VERSION 5.8 ;
BUSBITCHARS "[]" ;
DIVIDERCHAR "/" ;
UNITS
    DATABASE MICRONS 1000 ;
END UNITS

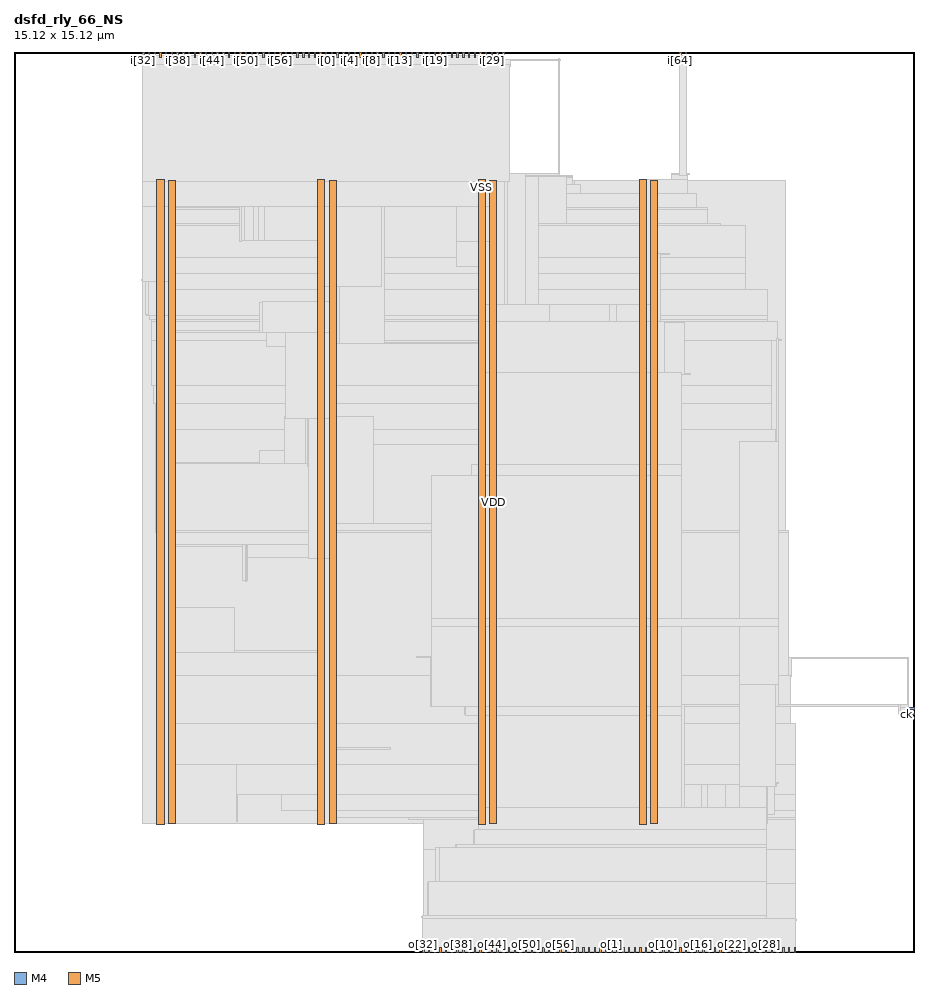
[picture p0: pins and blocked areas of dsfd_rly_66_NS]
MACRO dsfd_rly_66_NS
  FOREIGN dsfd_rly_66_NS 0 0 ;
  CLASS BLOCK ;
  SIZE 15.12 BY 15.12 ;
  PIN ck
    DIRECTION INPUT ;
    USE SIGNAL ;
    PORT
      LAYER M4 ;
        RECT  15.036 3.984 15.12 4.008 ;
    END
  END ck
  PIN i[0]
    DIRECTION INPUT ;
    USE SIGNAL ;
    PORT
      LAYER M5 ;
        RECT  5.232 15.036 5.256 15.12 ;
    END
  END i[0]
  PIN i[10]
    DIRECTION INPUT ;
    USE SIGNAL ;
    PORT
      LAYER M5 ;
        RECT  6.192 15.036 6.216 15.12 ;
    END
  END i[10]
  PIN i[11]
    DIRECTION INPUT ;
    USE SIGNAL ;
    PORT
      LAYER M5 ;
        RECT  6.288 15.036 6.312 15.12 ;
    END
  END i[11]
  PIN i[12]
    DIRECTION INPUT ;
    USE SIGNAL ;
    PORT
      LAYER M5 ;
        RECT  6.384 15.036 6.408 15.12 ;
    END
  END i[12]
  PIN i[13]
    DIRECTION INPUT ;
    USE SIGNAL ;
    PORT
      LAYER M5 ;
        RECT  6.48 15.036 6.504 15.12 ;
    END
  END i[13]
  PIN i[14]
    DIRECTION INPUT ;
    USE SIGNAL ;
    PORT
      LAYER M5 ;
        RECT  6.576 15.036 6.6 15.12 ;
    END
  END i[14]
  PIN i[15]
    DIRECTION INPUT ;
    USE SIGNAL ;
    PORT
      LAYER M5 ;
        RECT  6.672 15.036 6.696 15.12 ;
    END
  END i[15]
  PIN i[16]
    DIRECTION INPUT ;
    USE SIGNAL ;
    PORT
      LAYER M5 ;
        RECT  6.768 15.036 6.792 15.12 ;
    END
  END i[16]
  PIN i[17]
    DIRECTION INPUT ;
    USE SIGNAL ;
    PORT
      LAYER M5 ;
        RECT  6.864 15.036 6.888 15.12 ;
    END
  END i[17]
  PIN i[18]
    DIRECTION INPUT ;
    USE SIGNAL ;
    PORT
      LAYER M5 ;
        RECT  6.96 15.036 6.984 15.12 ;
    END
  END i[18]
  PIN i[19]
    DIRECTION INPUT ;
    USE SIGNAL ;
    PORT
      LAYER M5 ;
        RECT  7.056 15.036 7.08 15.12 ;
    END
  END i[19]
  PIN i[1]
    DIRECTION INPUT ;
    USE SIGNAL ;
    PORT
      LAYER M5 ;
        RECT  5.328 15.036 5.352 15.12 ;
    END
  END i[1]
  PIN i[20]
    DIRECTION INPUT ;
    USE SIGNAL ;
    PORT
      LAYER M5 ;
        RECT  7.152 15.036 7.176 15.12 ;
    END
  END i[20]
  PIN i[21]
    DIRECTION INPUT ;
    USE SIGNAL ;
    PORT
      LAYER M5 ;
        RECT  7.248 15.036 7.272 15.12 ;
    END
  END i[21]
  PIN i[22]
    DIRECTION INPUT ;
    USE SIGNAL ;
    PORT
      LAYER M5 ;
        RECT  7.344 15.036 7.368 15.12 ;
    END
  END i[22]
  PIN i[23]
    DIRECTION INPUT ;
    USE SIGNAL ;
    PORT
      LAYER M5 ;
        RECT  7.44 15.036 7.464 15.12 ;
    END
  END i[23]
  PIN i[24]
    DIRECTION INPUT ;
    USE SIGNAL ;
    PORT
      LAYER M5 ;
        RECT  7.536 15.036 7.56 15.12 ;
    END
  END i[24]
  PIN i[25]
    DIRECTION INPUT ;
    USE SIGNAL ;
    PORT
      LAYER M5 ;
        RECT  7.632 15.036 7.656 15.12 ;
    END
  END i[25]
  PIN i[26]
    DIRECTION INPUT ;
    USE SIGNAL ;
    PORT
      LAYER M5 ;
        RECT  7.728 15.036 7.752 15.12 ;
    END
  END i[26]
  PIN i[27]
    DIRECTION INPUT ;
    USE SIGNAL ;
    PORT
      LAYER M5 ;
        RECT  7.824 15.036 7.848 15.12 ;
    END
  END i[27]
  PIN i[28]
    DIRECTION INPUT ;
    USE SIGNAL ;
    PORT
      LAYER M5 ;
        RECT  7.92 15.036 7.944 15.12 ;
    END
  END i[28]
  PIN i[29]
    DIRECTION INPUT ;
    USE SIGNAL ;
    PORT
      LAYER M5 ;
        RECT  8.016 15.036 8.04 15.12 ;
    END
  END i[29]
  PIN i[2]
    DIRECTION INPUT ;
    USE SIGNAL ;
    PORT
      LAYER M5 ;
        RECT  5.424 15.036 5.448 15.12 ;
    END
  END i[2]
  PIN i[30]
    DIRECTION INPUT ;
    USE SIGNAL ;
    PORT
      LAYER M5 ;
        RECT  8.112 15.036 8.136 15.12 ;
    END
  END i[30]
  PIN i[31]
    DIRECTION INPUT ;
    USE SIGNAL ;
    PORT
      LAYER M5 ;
        RECT  8.208 15.036 8.232 15.12 ;
    END
  END i[31]
  PIN i[32]
    DIRECTION INPUT ;
    USE SIGNAL ;
    PORT
      LAYER M5 ;
        RECT  2.16 15.036 2.184 15.12 ;
    END
  END i[32]
  PIN i[33]
    DIRECTION INPUT ;
    USE SIGNAL ;
    PORT
      LAYER M5 ;
        RECT  2.256 15.036 2.28 15.12 ;
    END
  END i[33]
  PIN i[34]
    DIRECTION INPUT ;
    USE SIGNAL ;
    PORT
      LAYER M5 ;
        RECT  2.352 15.036 2.376 15.12 ;
    END
  END i[34]
  PIN i[35]
    DIRECTION INPUT ;
    USE SIGNAL ;
    PORT
      LAYER M5 ;
        RECT  2.448 15.036 2.472 15.12 ;
    END
  END i[35]
  PIN i[36]
    DIRECTION INPUT ;
    USE SIGNAL ;
    PORT
      LAYER M5 ;
        RECT  2.544 15.036 2.568 15.12 ;
    END
  END i[36]
  PIN i[37]
    DIRECTION INPUT ;
    USE SIGNAL ;
    PORT
      LAYER M5 ;
        RECT  2.64 15.036 2.664 15.12 ;
    END
  END i[37]
  PIN i[38]
    DIRECTION INPUT ;
    USE SIGNAL ;
    PORT
      LAYER M5 ;
        RECT  2.736 15.036 2.76 15.12 ;
    END
  END i[38]
  PIN i[39]
    DIRECTION INPUT ;
    USE SIGNAL ;
    PORT
      LAYER M5 ;
        RECT  2.832 15.036 2.856 15.12 ;
    END
  END i[39]
  PIN i[3]
    DIRECTION INPUT ;
    USE SIGNAL ;
    PORT
      LAYER M5 ;
        RECT  5.52 15.036 5.544 15.12 ;
    END
  END i[3]
  PIN i[40]
    DIRECTION INPUT ;
    USE SIGNAL ;
    PORT
      LAYER M5 ;
        RECT  2.928 15.036 2.952 15.12 ;
    END
  END i[40]
  PIN i[41]
    DIRECTION INPUT ;
    USE SIGNAL ;
    PORT
      LAYER M5 ;
        RECT  3.024 15.036 3.048 15.12 ;
    END
  END i[41]
  PIN i[42]
    DIRECTION INPUT ;
    USE SIGNAL ;
    PORT
      LAYER M5 ;
        RECT  3.12 15.036 3.144 15.12 ;
    END
  END i[42]
  PIN i[43]
    DIRECTION INPUT ;
    USE SIGNAL ;
    PORT
      LAYER M5 ;
        RECT  3.216 15.036 3.24 15.12 ;
    END
  END i[43]
  PIN i[44]
    DIRECTION INPUT ;
    USE SIGNAL ;
    PORT
      LAYER M5 ;
        RECT  3.312 15.036 3.336 15.12 ;
    END
  END i[44]
  PIN i[45]
    DIRECTION INPUT ;
    USE SIGNAL ;
    PORT
      LAYER M5 ;
        RECT  3.408 15.036 3.432 15.12 ;
    END
  END i[45]
  PIN i[46]
    DIRECTION INPUT ;
    USE SIGNAL ;
    PORT
      LAYER M5 ;
        RECT  3.504 15.036 3.528 15.12 ;
    END
  END i[46]
  PIN i[47]
    DIRECTION INPUT ;
    USE SIGNAL ;
    PORT
      LAYER M5 ;
        RECT  3.6 15.036 3.624 15.12 ;
    END
  END i[47]
  PIN i[48]
    DIRECTION INPUT ;
    USE SIGNAL ;
    PORT
      LAYER M5 ;
        RECT  3.696 15.036 3.72 15.12 ;
    END
  END i[48]
  PIN i[49]
    DIRECTION INPUT ;
    USE SIGNAL ;
    PORT
      LAYER M5 ;
        RECT  3.792 15.036 3.816 15.12 ;
    END
  END i[49]
  PIN i[4]
    DIRECTION INPUT ;
    USE SIGNAL ;
    PORT
      LAYER M5 ;
        RECT  5.616 15.036 5.64 15.12 ;
    END
  END i[4]
  PIN i[50]
    DIRECTION INPUT ;
    USE SIGNAL ;
    PORT
      LAYER M5 ;
        RECT  3.888 15.036 3.912 15.12 ;
    END
  END i[50]
  PIN i[51]
    DIRECTION INPUT ;
    USE SIGNAL ;
    PORT
      LAYER M5 ;
        RECT  3.984 15.036 4.008 15.12 ;
    END
  END i[51]
  PIN i[52]
    DIRECTION INPUT ;
    USE SIGNAL ;
    PORT
      LAYER M5 ;
        RECT  4.08 15.036 4.104 15.12 ;
    END
  END i[52]
  PIN i[53]
    DIRECTION INPUT ;
    USE SIGNAL ;
    PORT
      LAYER M5 ;
        RECT  4.176 15.036 4.2 15.12 ;
    END
  END i[53]
  PIN i[54]
    DIRECTION INPUT ;
    USE SIGNAL ;
    PORT
      LAYER M5 ;
        RECT  4.272 15.036 4.296 15.12 ;
    END
  END i[54]
  PIN i[55]
    DIRECTION INPUT ;
    USE SIGNAL ;
    PORT
      LAYER M5 ;
        RECT  4.368 15.036 4.392 15.12 ;
    END
  END i[55]
  PIN i[56]
    DIRECTION INPUT ;
    USE SIGNAL ;
    PORT
      LAYER M5 ;
        RECT  4.464 15.036 4.488 15.12 ;
    END
  END i[56]
  PIN i[57]
    DIRECTION INPUT ;
    USE SIGNAL ;
    PORT
      LAYER M5 ;
        RECT  4.56 15.036 4.584 15.12 ;
    END
  END i[57]
  PIN i[58]
    DIRECTION INPUT ;
    USE SIGNAL ;
    PORT
      LAYER M5 ;
        RECT  4.656 15.036 4.68 15.12 ;
    END
  END i[58]
  PIN i[59]
    DIRECTION INPUT ;
    USE SIGNAL ;
    PORT
      LAYER M5 ;
        RECT  4.752 15.036 4.776 15.12 ;
    END
  END i[59]
  PIN i[5]
    DIRECTION INPUT ;
    USE SIGNAL ;
    PORT
      LAYER M5 ;
        RECT  5.712 15.036 5.736 15.12 ;
    END
  END i[5]
  PIN i[60]
    DIRECTION INPUT ;
    USE SIGNAL ;
    PORT
      LAYER M5 ;
        RECT  4.848 15.036 4.872 15.12 ;
    END
  END i[60]
  PIN i[61]
    DIRECTION INPUT ;
    USE SIGNAL ;
    PORT
      LAYER M5 ;
        RECT  4.944 15.036 4.968 15.12 ;
    END
  END i[61]
  PIN i[62]
    DIRECTION INPUT ;
    USE SIGNAL ;
    PORT
      LAYER M5 ;
        RECT  5.04 15.036 5.064 15.12 ;
    END
  END i[62]
  PIN i[63]
    DIRECTION INPUT ;
    USE SIGNAL ;
    PORT
      LAYER M5 ;
        RECT  5.136 15.036 5.16 15.12 ;
    END
  END i[63]
  PIN i[64]
    DIRECTION INPUT ;
    USE SIGNAL ;
    PORT
      LAYER M5 ;
        RECT  11.184 15.036 11.208 15.12 ;
    END
  END i[64]
  PIN i[65]
    DIRECTION INPUT ;
    USE SIGNAL ;
    PORT
      LAYER M5 ;
        RECT  11.28 15.036 11.304 15.12 ;
    END
  END i[65]
  PIN i[6]
    DIRECTION INPUT ;
    USE SIGNAL ;
    PORT
      LAYER M5 ;
        RECT  5.808 15.036 5.832 15.12 ;
    END
  END i[6]
  PIN i[7]
    DIRECTION INPUT ;
    USE SIGNAL ;
    PORT
      LAYER M5 ;
        RECT  5.904 15.036 5.928 15.12 ;
    END
  END i[7]
  PIN i[8]
    DIRECTION INPUT ;
    USE SIGNAL ;
    PORT
      LAYER M5 ;
        RECT  6 15.036 6.024 15.12 ;
    END
  END i[8]
  PIN i[9]
    DIRECTION INPUT ;
    USE SIGNAL ;
    PORT
      LAYER M5 ;
        RECT  6.096 15.036 6.12 15.12 ;
    END
  END i[9]
  PIN o[0]
    DIRECTION OUTPUT ;
    USE SIGNAL ;
    PORT
      LAYER M5 ;
        RECT  9.936 0 9.96 0.084 ;
    END
  END o[0]
  PIN o[10]
    DIRECTION OUTPUT ;
    USE SIGNAL ;
    PORT
      LAYER M5 ;
        RECT  10.896 0 10.92 0.084 ;
    END
  END o[10]
  PIN o[11]
    DIRECTION OUTPUT ;
    USE SIGNAL ;
    PORT
      LAYER M5 ;
        RECT  10.992 0 11.016 0.084 ;
    END
  END o[11]
  PIN o[12]
    DIRECTION OUTPUT ;
    USE SIGNAL ;
    PORT
      LAYER M5 ;
        RECT  11.088 0 11.112 0.084 ;
    END
  END o[12]
  PIN o[13]
    DIRECTION OUTPUT ;
    USE SIGNAL ;
    PORT
      LAYER M5 ;
        RECT  11.184 0 11.208 0.084 ;
    END
  END o[13]
  PIN o[14]
    DIRECTION OUTPUT ;
    USE SIGNAL ;
    PORT
      LAYER M5 ;
        RECT  11.28 0 11.304 0.084 ;
    END
  END o[14]
  PIN o[15]
    DIRECTION OUTPUT ;
    USE SIGNAL ;
    PORT
      LAYER M5 ;
        RECT  11.376 0 11.4 0.084 ;
    END
  END o[15]
  PIN o[16]
    DIRECTION OUTPUT ;
    USE SIGNAL ;
    PORT
      LAYER M5 ;
        RECT  11.472 0 11.496 0.084 ;
    END
  END o[16]
  PIN o[17]
    DIRECTION OUTPUT ;
    USE SIGNAL ;
    PORT
      LAYER M5 ;
        RECT  11.568 0 11.592 0.084 ;
    END
  END o[17]
  PIN o[18]
    DIRECTION OUTPUT ;
    USE SIGNAL ;
    PORT
      LAYER M5 ;
        RECT  11.664 0 11.688 0.084 ;
    END
  END o[18]
  PIN o[19]
    DIRECTION OUTPUT ;
    USE SIGNAL ;
    PORT
      LAYER M5 ;
        RECT  11.76 0 11.784 0.084 ;
    END
  END o[19]
  PIN o[1]
    DIRECTION OUTPUT ;
    USE SIGNAL ;
    PORT
      LAYER M5 ;
        RECT  10.032 0 10.056 0.084 ;
    END
  END o[1]
  PIN o[20]
    DIRECTION OUTPUT ;
    USE SIGNAL ;
    PORT
      LAYER M5 ;
        RECT  11.856 0 11.88 0.084 ;
    END
  END o[20]
  PIN o[21]
    DIRECTION OUTPUT ;
    USE SIGNAL ;
    PORT
      LAYER M5 ;
        RECT  11.952 0 11.976 0.084 ;
    END
  END o[21]
  PIN o[22]
    DIRECTION OUTPUT ;
    USE SIGNAL ;
    PORT
      LAYER M5 ;
        RECT  12.048 0 12.072 0.084 ;
    END
  END o[22]
  PIN o[23]
    DIRECTION OUTPUT ;
    USE SIGNAL ;
    PORT
      LAYER M5 ;
        RECT  12.144 0 12.168 0.084 ;
    END
  END o[23]
  PIN o[24]
    DIRECTION OUTPUT ;
    USE SIGNAL ;
    PORT
      LAYER M5 ;
        RECT  12.24 0 12.264 0.084 ;
    END
  END o[24]
  PIN o[25]
    DIRECTION OUTPUT ;
    USE SIGNAL ;
    PORT
      LAYER M5 ;
        RECT  12.336 0 12.36 0.084 ;
    END
  END o[25]
  PIN o[26]
    DIRECTION OUTPUT ;
    USE SIGNAL ;
    PORT
      LAYER M5 ;
        RECT  12.432 0 12.456 0.084 ;
    END
  END o[26]
  PIN o[27]
    DIRECTION OUTPUT ;
    USE SIGNAL ;
    PORT
      LAYER M5 ;
        RECT  12.528 0 12.552 0.084 ;
    END
  END o[27]
  PIN o[28]
    DIRECTION OUTPUT ;
    USE SIGNAL ;
    PORT
      LAYER M5 ;
        RECT  12.624 0 12.648 0.084 ;
    END
  END o[28]
  PIN o[29]
    DIRECTION OUTPUT ;
    USE SIGNAL ;
    PORT
      LAYER M5 ;
        RECT  12.72 0 12.744 0.084 ;
    END
  END o[29]
  PIN o[2]
    DIRECTION OUTPUT ;
    USE SIGNAL ;
    PORT
      LAYER M5 ;
        RECT  10.128 0 10.152 0.084 ;
    END
  END o[2]
  PIN o[30]
    DIRECTION OUTPUT ;
    USE SIGNAL ;
    PORT
      LAYER M5 ;
        RECT  12.816 0 12.84 0.084 ;
    END
  END o[30]
  PIN o[31]
    DIRECTION OUTPUT ;
    USE SIGNAL ;
    PORT
      LAYER M5 ;
        RECT  12.912 0 12.936 0.084 ;
    END
  END o[31]
  PIN o[32]
    DIRECTION OUTPUT ;
    USE SIGNAL ;
    PORT
      LAYER M5 ;
        RECT  6.864 0 6.888 0.084 ;
    END
  END o[32]
  PIN o[33]
    DIRECTION OUTPUT ;
    USE SIGNAL ;
    PORT
      LAYER M5 ;
        RECT  6.96 0 6.984 0.084 ;
    END
  END o[33]
  PIN o[34]
    DIRECTION OUTPUT ;
    USE SIGNAL ;
    PORT
      LAYER M5 ;
        RECT  7.056 0 7.08 0.084 ;
    END
  END o[34]
  PIN o[35]
    DIRECTION OUTPUT ;
    USE SIGNAL ;
    PORT
      LAYER M5 ;
        RECT  7.152 0 7.176 0.084 ;
    END
  END o[35]
  PIN o[36]
    DIRECTION OUTPUT ;
    USE SIGNAL ;
    PORT
      LAYER M5 ;
        RECT  7.248 0 7.272 0.084 ;
    END
  END o[36]
  PIN o[37]
    DIRECTION OUTPUT ;
    USE SIGNAL ;
    PORT
      LAYER M5 ;
        RECT  7.344 0 7.368 0.084 ;
    END
  END o[37]
  PIN o[38]
    DIRECTION OUTPUT ;
    USE SIGNAL ;
    PORT
      LAYER M5 ;
        RECT  7.44 0 7.464 0.084 ;
    END
  END o[38]
  PIN o[39]
    DIRECTION OUTPUT ;
    USE SIGNAL ;
    PORT
      LAYER M5 ;
        RECT  7.536 0 7.56 0.084 ;
    END
  END o[39]
  PIN o[3]
    DIRECTION OUTPUT ;
    USE SIGNAL ;
    PORT
      LAYER M5 ;
        RECT  10.224 0 10.248 0.084 ;
    END
  END o[3]
  PIN o[40]
    DIRECTION OUTPUT ;
    USE SIGNAL ;
    PORT
      LAYER M5 ;
        RECT  7.632 0 7.656 0.084 ;
    END
  END o[40]
  PIN o[41]
    DIRECTION OUTPUT ;
    USE SIGNAL ;
    PORT
      LAYER M5 ;
        RECT  7.728 0 7.752 0.084 ;
    END
  END o[41]
  PIN o[42]
    DIRECTION OUTPUT ;
    USE SIGNAL ;
    PORT
      LAYER M5 ;
        RECT  7.824 0 7.848 0.084 ;
    END
  END o[42]
  PIN o[43]
    DIRECTION OUTPUT ;
    USE SIGNAL ;
    PORT
      LAYER M5 ;
        RECT  7.92 0 7.944 0.084 ;
    END
  END o[43]
  PIN o[44]
    DIRECTION OUTPUT ;
    USE SIGNAL ;
    PORT
      LAYER M5 ;
        RECT  8.016 0 8.04 0.084 ;
    END
  END o[44]
  PIN o[45]
    DIRECTION OUTPUT ;
    USE SIGNAL ;
    PORT
      LAYER M5 ;
        RECT  8.112 0 8.136 0.084 ;
    END
  END o[45]
  PIN o[46]
    DIRECTION OUTPUT ;
    USE SIGNAL ;
    PORT
      LAYER M5 ;
        RECT  8.208 0 8.232 0.084 ;
    END
  END o[46]
  PIN o[47]
    DIRECTION OUTPUT ;
    USE SIGNAL ;
    PORT
      LAYER M5 ;
        RECT  8.304 0 8.328 0.084 ;
    END
  END o[47]
  PIN o[48]
    DIRECTION OUTPUT ;
    USE SIGNAL ;
    PORT
      LAYER M5 ;
        RECT  8.4 0 8.424 0.084 ;
    END
  END o[48]
  PIN o[49]
    DIRECTION OUTPUT ;
    USE SIGNAL ;
    PORT
      LAYER M5 ;
        RECT  8.496 0 8.52 0.084 ;
    END
  END o[49]
  PIN o[4]
    DIRECTION OUTPUT ;
    USE SIGNAL ;
    PORT
      LAYER M5 ;
        RECT  10.32 0 10.344 0.084 ;
    END
  END o[4]
  PIN o[50]
    DIRECTION OUTPUT ;
    USE SIGNAL ;
    PORT
      LAYER M5 ;
        RECT  8.592 0 8.616 0.084 ;
    END
  END o[50]
  PIN o[51]
    DIRECTION OUTPUT ;
    USE SIGNAL ;
    PORT
      LAYER M5 ;
        RECT  8.688 0 8.712 0.084 ;
    END
  END o[51]
  PIN o[52]
    DIRECTION OUTPUT ;
    USE SIGNAL ;
    PORT
      LAYER M5 ;
        RECT  8.784 0 8.808 0.084 ;
    END
  END o[52]
  PIN o[53]
    DIRECTION OUTPUT ;
    USE SIGNAL ;
    PORT
      LAYER M5 ;
        RECT  8.88 0 8.904 0.084 ;
    END
  END o[53]
  PIN o[54]
    DIRECTION OUTPUT ;
    USE SIGNAL ;
    PORT
      LAYER M5 ;
        RECT  8.976 0 9 0.084 ;
    END
  END o[54]
  PIN o[55]
    DIRECTION OUTPUT ;
    USE SIGNAL ;
    PORT
      LAYER M5 ;
        RECT  9.072 0 9.096 0.084 ;
    END
  END o[55]
  PIN o[56]
    DIRECTION OUTPUT ;
    USE SIGNAL ;
    PORT
      LAYER M5 ;
        RECT  9.168 0 9.192 0.084 ;
    END
  END o[56]
  PIN o[57]
    DIRECTION OUTPUT ;
    USE SIGNAL ;
    PORT
      LAYER M5 ;
        RECT  9.264 0 9.288 0.084 ;
    END
  END o[57]
  PIN o[58]
    DIRECTION OUTPUT ;
    USE SIGNAL ;
    PORT
      LAYER M5 ;
        RECT  9.36 0 9.384 0.084 ;
    END
  END o[58]
  PIN o[59]
    DIRECTION OUTPUT ;
    USE SIGNAL ;
    PORT
      LAYER M5 ;
        RECT  9.456 0 9.48 0.084 ;
    END
  END o[59]
  PIN o[5]
    DIRECTION OUTPUT ;
    USE SIGNAL ;
    PORT
      LAYER M5 ;
        RECT  10.416 0 10.44 0.084 ;
    END
  END o[5]
  PIN o[60]
    DIRECTION OUTPUT ;
    USE SIGNAL ;
    PORT
      LAYER M5 ;
        RECT  9.552 0 9.576 0.084 ;
    END
  END o[60]
  PIN o[61]
    DIRECTION OUTPUT ;
    USE SIGNAL ;
    PORT
      LAYER M5 ;
        RECT  9.648 0 9.672 0.084 ;
    END
  END o[61]
  PIN o[62]
    DIRECTION OUTPUT ;
    USE SIGNAL ;
    PORT
      LAYER M5 ;
        RECT  9.744 0 9.768 0.084 ;
    END
  END o[62]
  PIN o[63]
    DIRECTION OUTPUT ;
    USE SIGNAL ;
    PORT
      LAYER M5 ;
        RECT  9.84 0 9.864 0.084 ;
    END
  END o[63]
  PIN o[64]
    DIRECTION OUTPUT ;
    USE SIGNAL ;
    PORT
      LAYER M5 ;
        RECT  13.008 0 13.032 0.084 ;
    END
  END o[64]
  PIN o[65]
    DIRECTION OUTPUT ;
    USE SIGNAL ;
    PORT
      LAYER M5 ;
        RECT  13.104 0 13.128 0.084 ;
    END
  END o[65]
  PIN o[6]
    DIRECTION OUTPUT ;
    USE SIGNAL ;
    PORT
      LAYER M5 ;
        RECT  10.512 0 10.536 0.084 ;
    END
  END o[6]
  PIN o[7]
    DIRECTION OUTPUT ;
    USE SIGNAL ;
    PORT
      LAYER M5 ;
        RECT  10.608 0 10.632 0.084 ;
    END
  END o[7]
  PIN o[8]
    DIRECTION OUTPUT ;
    USE SIGNAL ;
    PORT
      LAYER M5 ;
        RECT  10.704 0 10.728 0.084 ;
    END
  END o[8]
  PIN o[9]
    DIRECTION OUTPUT ;
    USE SIGNAL ;
    PORT
      LAYER M5 ;
        RECT  10.8 0 10.824 0.084 ;
    END
  END o[9]
  PIN rs
    DIRECTION INPUT ;
    USE SIGNAL ;
    PORT
      LAYER M4 ;
        RECT  15.036 4.08 15.12 4.104 ;
    END
  END rs
  PIN VDD
    DIRECTION INOUT ;
    USE POWER ;
    PORT
      LAYER M5 ;
        RECT  10.692 2.151 10.812 12.969 ;
        RECT  7.992 2.151 8.112 12.969 ;
        RECT  5.292 2.151 5.412 12.969 ;
        RECT  2.592 2.151 2.712 12.969 ;
    END
  END VDD
  PIN VSS
    DIRECTION INOUT ;
    USE GROUND ;
    PORT
      LAYER M5 ;
        RECT  10.5 2.137 10.62 12.983 ;
        RECT  7.8 2.137 7.92 12.983 ;
        RECT  5.1 2.137 5.22 12.983 ;
        RECT  2.4 2.137 2.52 12.983 ;
    END
  END VSS
  OBS
    LAYER RVTN ;
     RECT  2.16 2.16 12.96 2.295 ;
     RECT  2.16 2.565 12.96 2.835 ;
     RECT  2.16 3.105 12.96 3.375 ;
     RECT  2.16 3.645 12.96 3.915 ;
     RECT  2.16 4.185 12.96 4.455 ;
     RECT  2.16 4.725 12.96 4.995 ;
     RECT  2.16 5.265 12.96 5.535 ;
     RECT  2.16 5.805 12.96 6.075 ;
     RECT  2.16 6.345 12.96 6.615 ;
     RECT  2.16 6.885 12.96 7.155 ;
     RECT  2.16 7.425 12.96 7.695 ;
     RECT  2.16 7.965 12.96 8.235 ;
     RECT  2.16 8.505 12.96 8.775 ;
     RECT  2.16 9.045 12.96 9.315 ;
     RECT  2.16 9.585 12.96 9.855 ;
     RECT  2.16 10.125 12.96 10.395 ;
     RECT  2.16 10.665 12.96 10.935 ;
     RECT  2.16 11.205 12.96 11.475 ;
     RECT  2.16 11.745 12.96 12.015 ;
     RECT  2.16 12.285 12.96 12.555 ;
     RECT  2.16 12.825 12.96 12.96 ;
    LAYER RVTP ;
     RECT  2.16 2.295 12.96 2.565 ;
     RECT  2.16 2.835 12.96 3.105 ;
     RECT  2.16 3.375 12.96 3.645 ;
     RECT  2.16 3.915 12.96 4.185 ;
     RECT  2.16 4.455 12.96 4.725 ;
     RECT  2.16 4.995 12.96 5.265 ;
     RECT  2.16 5.535 12.96 5.805 ;
     RECT  2.16 6.075 12.96 6.345 ;
     RECT  2.16 6.615 12.96 6.885 ;
     RECT  2.16 7.155 12.96 7.425 ;
     RECT  2.16 7.695 12.96 7.965 ;
     RECT  2.16 8.235 12.96 8.505 ;
     RECT  2.16 8.775 12.96 9.045 ;
     RECT  2.16 9.315 12.96 9.585 ;
     RECT  2.16 9.855 12.96 10.125 ;
     RECT  2.16 10.395 12.96 10.665 ;
     RECT  2.16 10.935 12.96 11.205 ;
     RECT  2.16 11.475 12.96 11.745 ;
     RECT  2.16 12.015 12.96 12.285 ;
     RECT  2.16 12.555 12.96 12.825 ;
    LAYER M1 ;
     RECT  2.16 2.151 12.96 12.969 ;
    LAYER M2 ;
     RECT  2.16 2.151 8.815 12.969 ;
     RECT  8.815 2.106 9.419 12.969 ;
     RECT  9.419 2.151 12.96 12.969 ;
     RECT  12.96 2.61 13.019 2.628 ;
     RECT  12.96 7.056 13.019 7.074 ;
     RECT  12.96 4.626 13.055 4.95 ;
     RECT  12.96 3.816 13.127 3.834 ;
     RECT  13.055 4.932 15.035 4.95 ;
    LAYER M3 ;
     RECT  12.132 0.091 13.05 0.139 ;
     RECT  9.828 0.091 9.846 0.235 ;
     RECT  10.656 0.091 10.674 0.475 ;
     RECT  12.024 0.139 13.05 0.523 ;
     RECT  7.056 0.523 7.506 0.571 ;
     RECT  9.828 0.235 9.882 0.571 ;
     RECT  10.656 0.475 10.998 0.571 ;
     RECT  9.18 0.571 10.998 1.147 ;
     RECT  11.988 0.523 13.122 1.147 ;
     RECT  6.876 0.571 7.506 1.723 ;
     RECT  8.316 0.571 8.334 1.723 ;
     RECT  9.18 1.147 13.122 1.723 ;
     RECT  6.876 1.723 13.122 2.227 ;
     RECT  5.115 2.143 5.205 2.263 ;
     RECT  6.624 2.227 13.122 2.263 ;
     RECT  5.115 2.263 13.122 2.371 ;
     RECT  2.415 2.143 2.505 2.413 ;
     RECT  3.744 2.191 3.762 2.641 ;
     RECT  4.5 2.371 13.122 2.641 ;
     RECT  2.415 2.413 2.697 3.145 ;
     RECT  3.744 2.641 13.122 3.145 ;
     RECT  2.415 3.145 13.122 3.839 ;
     RECT  14.868 3.979 14.886 4.075 ;
     RECT  14.868 4.075 15.03 4.157 ;
     RECT  2.415 3.839 13.05 4.649 ;
     RECT  15.012 4.157 15.03 4.955 ;
     RECT  2.415 4.649 13.014 7.051 ;
     RECT  2.376 7.051 13.014 7.079 ;
     RECT  2.376 7.079 12.798 8.771 ;
     RECT  2.376 8.771 12.726 9.211 ;
     RECT  2.34 9.211 12.726 9.517 ;
     RECT  2.304 9.517 12.726 10.267 ;
     RECT  2.304 10.267 12.834 10.589 ;
     RECT  2.304 10.589 12.654 10.633 ;
     RECT  2.268 10.633 12.654 10.699 ;
     RECT  2.232 10.699 12.654 11.129 ;
     RECT  2.232 11.129 12.294 11.399 ;
     RECT  2.268 11.399 12.294 11.669 ;
     RECT  2.304 11.669 12.294 12.209 ;
     RECT  2.304 12.209 11.862 12.245 ;
     RECT  2.304 12.245 11.646 12.479 ;
     RECT  2.34 12.479 11.646 12.515 ;
     RECT  2.34 12.515 11.466 12.749 ;
     RECT  2.34 12.749 9.522 12.893 ;
     RECT  10.515 12.749 11.322 12.977 ;
     RECT  2.34 12.893 9.378 13.037 ;
     RECT  2.34 13.037 9.162 13.085 ;
     RECT  11.052 12.977 11.322 13.085 ;
     RECT  5.004 13.085 5.454 13.133 ;
     RECT  7.956 13.085 8.226 13.133 ;
     RECT  8.208 13.133 8.226 13.181 ;
     RECT  2.34 13.085 2.826 13.229 ;
     RECT  2.808 13.229 2.826 13.709 ;
     RECT  3.744 13.085 3.906 13.709 ;
     RECT  3.816 13.709 3.906 14.237 ;
     RECT  3.888 14.237 3.906 14.717 ;
     RECT  5.076 13.133 5.094 14.765 ;
     RECT  9.144 13.085 9.162 15.005 ;
    LAYER M4 ;
     RECT  2.149 11.28 2.204 11.304 ;
     RECT  2.321 13.104 2.329 13.128 ;
     RECT  2.204 10.704 2.408 11.304 ;
     RECT  2.329 13.104 2.408 13.224 ;
     RECT  2.408 2.148 2.512 13.224 ;
     RECT  2.512 2.418 2.704 13.224 ;
     RECT  2.704 12.528 2.78 13.224 ;
     RECT  2.704 5.04 3.701 5.784 ;
     RECT  2.78 12.528 3.781 13.704 ;
     RECT  3.781 11.952 3.805 13.704 ;
     RECT  2.704 6.816 3.836 6.84 ;
     RECT  3.805 11.952 3.877 14.232 ;
     RECT  3.836 6.24 3.923 6.84 ;
     RECT  3.877 11.952 4.019 14.712 ;
     RECT  4.019 11.952 4.115 14.232 ;
     RECT  2.704 10.416 4.124 10.44 ;
     RECT  2.704 8.208 4.129 8.232 ;
     RECT  4.115 11.952 4.211 13.704 ;
     RECT  4.124 10.416 4.237 10.92 ;
     RECT  4.129 8.208 4.549 8.424 ;
     RECT  4.549 8.208 4.892 9 ;
     RECT  4.237 10.176 4.892 10.92 ;
     RECT  4.892 8.208 4.933 10.92 ;
     RECT  3.701 5.04 5.108 5.064 ;
     RECT  3.923 6.624 5.108 6.84 ;
     RECT  4.933 8.16 5.108 10.92 ;
     RECT  4.211 11.952 5.108 13.128 ;
     RECT  5.065 14.736 5.171 14.76 ;
     RECT  5.108 2.148 5.212 13.128 ;
     RECT  5.212 2.418 5.404 13.128 ;
     RECT  5.404 10.224 5.465 13.128 ;
     RECT  5.404 7.2 6.041 9 ;
     RECT  5.465 10.224 6.221 13.08 ;
     RECT  5.404 3.408 6.329 3.432 ;
     RECT  6.853 0.576 6.949 0.6 ;
     RECT  6.757 4.944 6.997 4.968 ;
     RECT  6.949 0.576 7.004 1.176 ;
     RECT  7.004 0.528 7.081 1.176 ;
     RECT  7.081 0.528 7.309 1.752 ;
     RECT  6.997 4.128 7.405 4.968 ;
     RECT  7.309 1.728 7.416 1.752 ;
     RECT  6.221 11.664 7.441 13.08 ;
     RECT  7.309 0.528 7.571 0.6 ;
     RECT  7.405 4.128 7.573 5.832 ;
     RECT  7.416 1.728 7.717 1.8 ;
     RECT  7.717 1.728 7.808 2.04 ;
     RECT  7.573 3.984 7.808 5.832 ;
     RECT  6.041 7.2 7.808 8.52 ;
     RECT  6.221 10.224 7.808 10.248 ;
     RECT  7.441 11.52 7.808 13.08 ;
     RECT  7.808 1.728 7.813 13.08 ;
     RECT  7.573 14.928 7.909 14.952 ;
     RECT  7.813 1.728 7.984 13.128 ;
     RECT  7.909 14.928 8.101 15 ;
     RECT  7.984 1.728 8.237 13.176 ;
     RECT  8.237 1.728 8.243 13.08 ;
     RECT  8.101 14.784 8.243 15 ;
     RECT  8.243 5.136 8.291 13.08 ;
     RECT  8.243 14.88 8.339 15 ;
     RECT  8.291 7.2 8.597 13.08 ;
     RECT  8.597 7.2 8.813 13.032 ;
     RECT  8.813 7.2 8.849 10.872 ;
     RECT  7.571 0.576 8.965 0.6 ;
     RECT  8.339 14.976 9.173 15 ;
     RECT  8.813 12.24 9.281 13.032 ;
     RECT  8.965 0.144 9.349 0.6 ;
     RECT  9.281 13.008 9.389 13.032 ;
     RECT  8.291 5.136 9.413 6.12 ;
     RECT  8.849 7.2 9.413 7.224 ;
     RECT  8.243 1.728 9.457 4.152 ;
     RECT  9.413 5.136 9.457 7.224 ;
     RECT  9.349 0.096 9.733 0.6 ;
     RECT  9.457 1.728 9.733 7.224 ;
     RECT  8.849 8.544 9.997 10.872 ;
     RECT  9.733 0.096 10.181 7.224 ;
     RECT  10.181 0.096 10.505 0.6 ;
     RECT  10.181 1.728 10.508 7.224 ;
     RECT  9.997 8.208 10.508 10.872 ;
     RECT  10.505 0.096 10.685 0.552 ;
     RECT  10.508 1.728 10.804 12.972 ;
     RECT  10.804 9.648 10.865 11.736 ;
     RECT  10.865 9.648 10.931 10.584 ;
     RECT  10.804 1.728 11.009 7.224 ;
     RECT  10.865 11.712 11.009 11.736 ;
     RECT  11.009 1.728 11.081 6.312 ;
     RECT  11.081 1.728 11.171 5.592 ;
     RECT  11.171 1.728 11.26 4.152 ;
     RECT  10.931 9.696 11.261 10.584 ;
     RECT  11.041 13.056 11.356 13.08 ;
     RECT  11.171 5.472 11.363 5.592 ;
     RECT  11.261 9.696 11.369 9.72 ;
     RECT  11.363 5.472 11.405 5.496 ;
     RECT  10.685 0.144 11.545 0.552 ;
     RECT  11.26 1.728 11.545 2.808 ;
     RECT  11.545 0.144 11.653 2.808 ;
     RECT  11.653 0.096 11.945 2.808 ;
     RECT  12.181 8.544 12.341 8.568 ;
     RECT  11.945 0.096 12.371 1.176 ;
     RECT  11.26 4.128 12.445 4.152 ;
     RECT  11.945 2.16 12.469 2.808 ;
     RECT  12.469 2.16 12.517 2.856 ;
     RECT  12.445 4.128 12.517 4.536 ;
     RECT  12.517 2.16 12.601 4.536 ;
     RECT  12.601 2.16 12.665 2.856 ;
     RECT  12.665 2.304 12.773 2.856 ;
     RECT  12.773 2.784 12.803 2.856 ;
     RECT  12.445 7.968 12.817 7.992 ;
     RECT  12.803 2.832 12.845 2.856 ;
     RECT  12.601 4.128 12.851 4.536 ;
     RECT  12.805 10.272 12.889 10.296 ;
     RECT  12.371 0.096 13.061 0.552 ;
     RECT  13.061 0.528 13.139 0.552 ;
     RECT  12.851 4.128 14.857 4.152 ;
     RECT  14.857 3.984 14.897 4.152 ;
     RECT  14.897 3.984 15.084 4.104 ;
    LAYER M5 ;
     RECT  6.864 0.016 13.128 0.563 ;
     RECT  6.864 0.563 12.648 0.611 ;
     RECT  6.96 0.611 12.648 1.187 ;
     RECT  7.152 1.187 12.648 1.763 ;
     RECT  7.44 1.763 12.648 1.811 ;
     RECT  7.728 1.811 12.648 2.051 ;
     RECT  2.4 2.137 2.52 2.151 ;
     RECT  5.1 2.137 5.22 2.151 ;
     RECT  7.8 2.051 12.648 2.435 ;
     RECT  12.192 2.435 12.648 2.773 ;
     RECT  7.8 2.435 11.208 3.973 ;
     RECT  7.584 3.973 11.208 4.117 ;
     RECT  12.192 2.773 12.792 4.501 ;
     RECT  7.008 4.117 11.208 5.461 ;
     RECT  12.192 4.501 12.84 5.461 ;
     RECT  7.008 5.461 12.84 5.603 ;
     RECT  5.1 2.151 5.412 6.613 ;
     RECT  3.888 6.229 3.912 6.851 ;
     RECT  7.008 5.603 11.208 8.003 ;
     RECT  7.68 8.003 11.208 8.195 ;
     RECT  12.192 5.603 12.84 8.579 ;
     RECT  4.944 6.613 5.412 8.965 ;
     RECT  7.8 8.195 11.208 9.731 ;
     RECT  12.816 8.579 12.84 10.307 ;
     RECT  4.56 8.965 5.412 10.405 ;
     RECT  7.8 9.731 10.92 10.595 ;
     RECT  2.4 2.151 2.712 10.693 ;
     RECT  7.8 10.595 9 10.883 ;
     RECT  10.128 10.595 10.812 10.883 ;
     RECT  4.176 10.405 5.412 10.931 ;
     RECT  5.1 10.931 5.412 11.173 ;
     RECT  2.256 10.693 2.712 11.269 ;
     RECT  7.8 10.883 8.112 11.941 ;
     RECT  2.16 11.269 2.712 12.517 ;
     RECT  3.792 11.941 3.816 12.517 ;
     RECT  5.1 11.173 6.168 12.517 ;
     RECT  7.44 11.941 8.112 12.517 ;
     RECT  2.16 12.517 8.112 12.949 ;
     RECT  10.5 10.883 10.812 12.983 ;
     RECT  2.16 12.949 8.328 14.915 ;
     RECT  2.16 14.915 8.232 15.056 ;
     RECT  11.184 13.045 11.304 15.056 ;
  END
END dsfd_rly_66_NS
END LIBRARY
